VERSION 5.7 ;
  NOWIREEXTENSIONATPIN ON ;
  DIVIDERCHAR "/" ;
  BUSBITCHARS "[]" ;
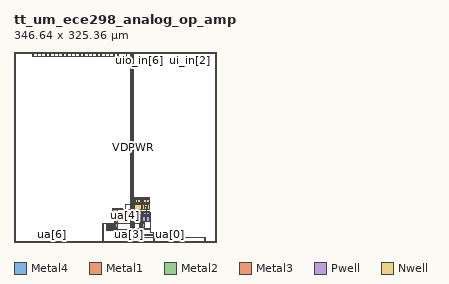
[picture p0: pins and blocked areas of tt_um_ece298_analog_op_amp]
MACRO tt_um_ece298_analog_op_amp
  CLASS BLOCK ;
  FOREIGN tt_um_ece298_analog_op_amp ;
  ORIGIN 0.000 0.000 ;
  SIZE 346.640 BY 325.360 ;
  PIN clk
    DIRECTION INPUT ;
    USE SIGNAL ;
    PORT
      LAYER Metal4 ;
        RECT 331.090 324.360 331.390 325.360 ;
    END
  END clk
  PIN ena
    DIRECTION INPUT ;
    USE SIGNAL ;
    PORT
      LAYER Metal4 ;
        RECT 338.370 324.360 338.670 325.360 ;
    END
  END ena
  PIN rst_n
    DIRECTION INPUT ;
    USE SIGNAL ;
    PORT
      LAYER Metal4 ;
        RECT 323.810 324.360 324.110 325.360 ;
    END
  END rst_n
  PIN ua[0]
    DIRECTION INOUT ;
    USE SIGNAL ;
    ANTENNAGATEAREA 44.799999 ;
    PORT
      LAYER Metal1 ;
        RECT 207.330 43.515 208.710 43.745 ;
        RECT 209.250 43.515 210.630 43.745 ;
        RECT 227.790 43.515 229.170 43.745 ;
        RECT 229.710 43.515 231.090 43.745 ;
        RECT 207.840 43.450 208.220 43.515 ;
        RECT 209.750 43.450 210.130 43.515 ;
        RECT 228.300 43.450 228.680 43.515 ;
        RECT 230.210 43.450 230.590 43.515 ;
        RECT 207.330 34.955 208.710 35.185 ;
        RECT 209.250 34.955 210.630 35.185 ;
        RECT 227.790 34.955 229.170 35.185 ;
        RECT 229.710 34.955 231.090 35.185 ;
      LAYER Metal2 ;
        RECT 205.230 45.550 205.730 45.650 ;
        RECT 205.230 45.250 228.680 45.550 ;
        RECT 205.230 45.150 205.730 45.250 ;
        RECT 207.840 43.820 208.220 45.250 ;
        RECT 228.300 43.820 228.680 45.250 ;
        RECT 207.380 43.520 210.580 43.820 ;
        RECT 227.840 43.520 231.040 43.820 ;
        RECT 207.840 43.450 208.220 43.520 ;
        RECT 209.750 43.450 210.130 43.520 ;
        RECT 228.300 43.450 228.680 43.520 ;
        RECT 230.210 43.450 230.590 43.520 ;
      LAYER Metal3 ;
        RECT 205.230 45.150 205.730 45.650 ;
        RECT 205.280 8.250 205.680 45.150 ;
        RECT 205.280 7.750 327.570 8.250 ;
      LAYER Metal4 ;
        RECT 326.820 1.000 327.820 8.250 ;
        RECT 325.820 0.000 328.820 1.000 ;
    END
  END ua[0]
  PIN ua[1]
    DIRECTION INOUT ;
    USE SIGNAL ;
    ANTENNAGATEAREA 44.799999 ;
    PORT
      LAYER Metal1 ;
        RECT 214.150 43.515 215.530 43.745 ;
        RECT 216.070 43.515 217.450 43.745 ;
        RECT 220.970 43.515 222.350 43.745 ;
        RECT 222.890 43.515 224.270 43.745 ;
        RECT 214.660 43.450 215.040 43.515 ;
        RECT 216.570 43.450 216.950 43.515 ;
        RECT 221.480 43.450 221.860 43.515 ;
        RECT 223.390 43.450 223.770 43.515 ;
        RECT 214.150 34.955 215.530 35.185 ;
        RECT 216.070 34.955 217.450 35.185 ;
        RECT 220.970 34.955 222.350 35.185 ;
        RECT 222.890 34.955 224.270 35.185 ;
      LAYER Metal2 ;
        RECT 216.570 43.820 217.580 43.840 ;
        RECT 214.200 43.740 217.580 43.820 ;
        RECT 221.020 43.740 224.220 43.820 ;
        RECT 214.200 43.520 224.220 43.740 ;
        RECT 214.660 43.450 215.040 43.520 ;
        RECT 216.570 43.450 221.860 43.520 ;
        RECT 223.390 43.450 223.770 43.520 ;
        RECT 216.570 43.350 217.580 43.450 ;
      LAYER Metal3 ;
        RECT 217.080 12.250 217.480 43.840 ;
        RECT 217.080 11.750 283.890 12.250 ;
      LAYER Metal4 ;
        RECT 283.140 1.000 284.140 12.250 ;
        RECT 282.140 0.000 285.140 1.000 ;
    END
  END ua[1]
  PIN ua[2]
    DIRECTION INOUT ;
    USE SIGNAL ;
    ANTENNADIFFAREA 12.880000 ;
    PORT
      LAYER Metal1 ;
        RECT 223.625 61.090 223.855 63.540 ;
        RECT 228.665 61.090 228.895 63.540 ;
        RECT 223.590 60.710 223.910 61.090 ;
        RECT 228.650 60.710 228.970 61.090 ;
        RECT 223.625 56.560 223.855 60.710 ;
        RECT 228.665 56.560 228.895 60.710 ;
        RECT 221.105 50.490 221.335 51.440 ;
        RECT 226.145 50.490 226.375 51.440 ;
        RECT 231.185 50.490 231.415 51.440 ;
        RECT 221.060 50.110 221.380 50.490 ;
        RECT 226.120 50.110 226.440 50.490 ;
        RECT 231.180 50.110 231.500 50.490 ;
        RECT 221.105 47.460 221.335 50.110 ;
        RECT 226.145 47.460 226.375 50.110 ;
        RECT 231.185 47.460 231.415 50.110 ;
      LAYER Metal2 ;
        RECT 223.560 60.750 229.000 61.050 ;
        RECT 233.030 50.450 233.530 50.550 ;
        RECT 221.030 50.150 233.530 50.450 ;
        RECT 233.030 50.050 233.530 50.150 ;
      LAYER Metal3 ;
        RECT 226.780 50.100 227.180 61.110 ;
        RECT 233.030 50.050 233.530 50.550 ;
        RECT 233.080 16.250 233.480 50.050 ;
        RECT 233.080 15.750 240.210 16.250 ;
      LAYER Metal4 ;
        RECT 239.460 1.000 240.460 16.250 ;
        RECT 238.460 0.000 241.460 1.000 ;
    END
  END ua[2]
  PIN ua[3]
    DIRECTION INOUT ;
    USE SIGNAL ;
    PORT
      LAYER Metal4 ;
        RECT 194.780 0.000 197.780 1.000 ;
    END
  END ua[3]
  PIN ua[4]
    DIRECTION INOUT ;
    USE SIGNAL ;
    ANTENNAGATEAREA 100.799995 ;
    ANTENNADIFFAREA 8.320000 ;
    PORT
      LAYER Metal1 ;
        RECT 159.570 31.645 159.930 31.650 ;
        RECT 161.490 31.645 161.850 31.650 ;
        RECT 163.410 31.645 163.770 31.650 ;
        RECT 165.330 31.645 165.690 31.650 ;
        RECT 159.060 31.415 160.440 31.645 ;
        RECT 160.980 31.415 162.360 31.645 ;
        RECT 162.900 31.415 164.280 31.645 ;
        RECT 164.820 31.415 166.200 31.645 ;
        RECT 169.940 31.415 171.320 31.645 ;
        RECT 215.640 31.415 217.020 31.645 ;
        RECT 217.560 31.415 218.940 31.645 ;
        RECT 219.480 31.415 220.860 31.645 ;
        RECT 221.400 31.415 222.780 31.645 ;
        RECT 159.560 31.350 159.940 31.415 ;
        RECT 161.480 31.350 161.860 31.415 ;
        RECT 163.400 31.350 163.780 31.415 ;
        RECT 165.320 31.350 165.700 31.415 ;
        RECT 170.155 31.345 171.105 31.415 ;
        RECT 216.140 31.350 216.520 31.415 ;
        RECT 218.060 31.350 218.440 31.415 ;
        RECT 219.980 31.350 220.360 31.415 ;
        RECT 221.900 31.350 222.280 31.415 ;
        RECT 160.595 28.380 160.825 31.240 ;
        RECT 164.435 28.380 164.665 31.240 ;
        RECT 160.530 28.020 160.890 28.380 ;
        RECT 164.370 28.020 164.730 28.380 ;
        RECT 160.595 23.260 160.825 28.020 ;
        RECT 164.435 23.260 164.665 28.020 ;
        RECT 159.060 22.855 160.440 23.085 ;
        RECT 160.980 22.855 162.360 23.085 ;
        RECT 162.900 22.855 164.280 23.085 ;
        RECT 164.820 22.855 166.200 23.085 ;
        RECT 169.940 22.855 171.320 23.085 ;
        RECT 215.640 22.855 217.020 23.085 ;
        RECT 217.560 22.855 218.940 23.085 ;
        RECT 219.480 22.855 220.860 23.085 ;
        RECT 221.400 22.855 222.780 23.085 ;
      LAYER Metal2 ;
        RECT 157.500 31.700 158.200 31.800 ;
        RECT 157.500 31.650 206.430 31.700 ;
        RECT 216.140 31.650 222.280 31.700 ;
        RECT 157.500 31.350 222.280 31.650 ;
        RECT 157.500 31.300 206.430 31.350 ;
        RECT 157.500 31.200 158.200 31.300 ;
        RECT 160.560 28.400 160.860 31.300 ;
        RECT 164.400 28.400 164.700 31.300 ;
        RECT 160.520 28.000 160.900 28.400 ;
        RECT 164.360 28.000 164.740 28.400 ;
      LAYER Metal3 ;
        RECT 157.500 31.750 158.200 31.800 ;
        RECT 152.350 31.250 158.200 31.750 ;
        RECT 152.350 2.400 152.850 31.250 ;
        RECT 157.500 31.200 158.200 31.250 ;
        RECT 152.100 0.500 153.100 2.400 ;
      LAYER Metal4 ;
        RECT 152.100 1.000 153.100 2.400 ;
        RECT 151.100 0.000 154.100 1.000 ;
    END
  END ua[4]
  PIN ua[5]
    DIRECTION INOUT ;
    USE SIGNAL ;
    PORT
      LAYER Metal4 ;
        RECT 107.420 0.000 110.420 1.000 ;
    END
  END ua[5]
  PIN ua[6]
    DIRECTION INOUT ;
    USE SIGNAL ;
    PORT
      LAYER Metal4 ;
        RECT 63.740 0.000 66.740 1.000 ;
    END
  END ua[6]
  PIN ua[7]
    DIRECTION INOUT ;
    USE SIGNAL ;
    PORT
      LAYER Metal4 ;
        RECT 20.060 0.000 23.060 1.000 ;
    END
  END ua[7]
  PIN ui_in[0]
    DIRECTION INPUT ;
    USE SIGNAL ;
    PORT
      LAYER Metal4 ;
        RECT 316.530 324.360 316.830 325.360 ;
    END
  END ui_in[0]
  PIN ui_in[1]
    DIRECTION INPUT ;
    USE SIGNAL ;
    PORT
      LAYER Metal4 ;
        RECT 309.250 324.360 309.550 325.360 ;
    END
  END ui_in[1]
  PIN ui_in[2]
    DIRECTION INPUT ;
    USE SIGNAL ;
    PORT
      LAYER Metal4 ;
        RECT 301.970 324.360 302.270 325.360 ;
    END
  END ui_in[2]
  PIN ui_in[3]
    DIRECTION INPUT ;
    USE SIGNAL ;
    PORT
      LAYER Metal4 ;
        RECT 294.690 324.360 294.990 325.360 ;
    END
  END ui_in[3]
  PIN ui_in[4]
    DIRECTION INPUT ;
    USE SIGNAL ;
    PORT
      LAYER Metal4 ;
        RECT 287.410 324.360 287.710 325.360 ;
    END
  END ui_in[4]
  PIN ui_in[5]
    DIRECTION INPUT ;
    USE SIGNAL ;
    PORT
      LAYER Metal4 ;
        RECT 280.130 324.360 280.430 325.360 ;
    END
  END ui_in[5]
  PIN ui_in[6]
    DIRECTION INPUT ;
    USE SIGNAL ;
    PORT
      LAYER Metal4 ;
        RECT 272.850 324.360 273.150 325.360 ;
    END
  END ui_in[6]
  PIN ui_in[7]
    DIRECTION INPUT ;
    USE SIGNAL ;
    PORT
      LAYER Metal4 ;
        RECT 265.570 324.360 265.870 325.360 ;
    END
  END ui_in[7]
  PIN uio_in[0]
    DIRECTION INPUT ;
    USE SIGNAL ;
    PORT
      LAYER Metal4 ;
        RECT 258.290 324.360 258.590 325.360 ;
    END
  END uio_in[0]
  PIN uio_in[1]
    DIRECTION INPUT ;
    USE SIGNAL ;
    PORT
      LAYER Metal4 ;
        RECT 251.010 324.360 251.310 325.360 ;
    END
  END uio_in[1]
  PIN uio_in[2]
    DIRECTION INPUT ;
    USE SIGNAL ;
    PORT
      LAYER Metal4 ;
        RECT 243.730 324.360 244.030 325.360 ;
    END
  END uio_in[2]
  PIN uio_in[3]
    DIRECTION INPUT ;
    USE SIGNAL ;
    PORT
      LAYER Metal4 ;
        RECT 236.450 324.360 236.750 325.360 ;
    END
  END uio_in[3]
  PIN uio_in[4]
    DIRECTION INPUT ;
    USE SIGNAL ;
    PORT
      LAYER Metal4 ;
        RECT 229.170 324.360 229.470 325.360 ;
    END
  END uio_in[4]
  PIN uio_in[5]
    DIRECTION INPUT ;
    USE SIGNAL ;
    PORT
      LAYER Metal4 ;
        RECT 221.890 324.360 222.190 325.360 ;
    END
  END uio_in[5]
  PIN uio_in[6]
    DIRECTION INPUT ;
    USE SIGNAL ;
    PORT
      LAYER Metal4 ;
        RECT 214.610 324.360 214.910 325.360 ;
    END
  END uio_in[6]
  PIN uio_in[7]
    DIRECTION INPUT ;
    USE SIGNAL ;
    PORT
      LAYER Metal4 ;
        RECT 207.330 324.360 207.630 325.360 ;
    END
  END uio_in[7]
  PIN uio_oe[0]
    DIRECTION OUTPUT ;
    USE SIGNAL ;
    ANTENNADIFFAREA 147.982391 ;
    PORT
      LAYER Pwell ;
        RECT 206.130 46.400 218.190 52.500 ;
        RECT 220.230 46.400 232.290 52.500 ;
        RECT 173.680 35.950 177.580 46.050 ;
        RECT 157.800 22.200 167.460 32.300 ;
        RECT 168.680 22.200 172.580 32.300 ;
        RECT 174.080 23.000 177.180 34.500 ;
        RECT 206.070 34.300 211.890 44.400 ;
        RECT 212.890 34.300 218.710 44.400 ;
        RECT 219.710 34.300 225.530 44.400 ;
        RECT 226.530 34.300 232.350 44.400 ;
        RECT 214.380 22.200 224.040 32.300 ;
      LAYER Metal1 ;
        RECT 206.315 52.085 218.005 52.315 ;
        RECT 206.315 46.815 206.545 52.085 ;
        RECT 217.775 46.815 218.005 52.085 ;
        RECT 206.315 46.585 218.005 46.815 ;
        RECT 220.415 52.085 232.105 52.315 ;
        RECT 220.415 46.815 220.645 52.085 ;
        RECT 231.875 46.815 232.105 52.085 ;
        RECT 220.415 46.585 232.105 46.815 ;
        RECT 173.865 45.635 177.395 45.865 ;
        RECT 173.865 36.430 174.095 45.635 ;
        RECT 177.165 36.430 177.395 45.635 ;
        RECT 206.320 44.550 206.570 46.585 ;
        RECT 231.850 44.550 232.100 46.585 ;
        RECT 206.130 44.020 232.290 44.550 ;
        RECT 173.865 36.365 174.280 36.430 ;
        RECT 176.980 36.365 177.395 36.430 ;
        RECT 173.865 34.100 177.395 36.365 ;
        RECT 206.255 43.985 211.705 44.020 ;
        RECT 206.255 34.715 206.485 43.985 ;
        RECT 211.475 34.715 211.705 43.985 ;
        RECT 206.255 34.485 211.705 34.715 ;
        RECT 213.075 43.985 218.525 44.020 ;
        RECT 213.075 34.715 213.305 43.985 ;
        RECT 218.295 34.715 218.525 43.985 ;
        RECT 213.075 34.485 218.525 34.715 ;
        RECT 219.895 43.985 225.345 44.020 ;
        RECT 219.895 34.715 220.125 43.985 ;
        RECT 225.115 34.715 225.345 43.985 ;
        RECT 219.895 34.485 225.345 34.715 ;
        RECT 226.715 43.985 232.165 44.020 ;
        RECT 226.715 34.715 226.945 43.985 ;
        RECT 231.935 34.715 232.165 43.985 ;
        RECT 226.715 34.485 232.165 34.715 ;
        RECT 173.865 34.085 177.400 34.100 ;
        RECT 173.865 33.865 174.495 34.085 ;
        RECT 173.860 32.115 174.495 33.865 ;
        RECT 157.985 31.885 174.495 32.115 ;
        RECT 157.985 31.240 158.215 31.885 ;
        RECT 167.045 31.240 169.095 31.885 ;
        RECT 157.985 25.380 158.905 31.240 ;
        RECT 162.515 25.380 162.745 31.240 ;
        RECT 166.355 28.800 169.095 31.240 ;
        RECT 166.355 27.440 169.130 28.800 ;
        RECT 169.555 27.440 169.785 31.240 ;
        RECT 166.355 27.040 169.785 27.440 ;
        RECT 166.355 25.380 169.130 27.040 ;
        RECT 157.985 25.020 158.970 25.380 ;
        RECT 162.450 25.020 162.810 25.380 ;
        RECT 166.290 25.020 169.130 25.380 ;
        RECT 157.985 23.260 158.905 25.020 ;
        RECT 162.515 23.260 162.745 25.020 ;
        RECT 166.355 24.135 169.130 25.020 ;
        RECT 166.355 23.260 169.095 24.135 ;
        RECT 169.555 23.260 169.785 27.040 ;
        RECT 172.165 24.000 174.495 31.885 ;
        RECT 175.140 24.000 176.120 24.105 ;
        RECT 176.765 24.000 177.400 34.085 ;
        RECT 214.570 32.550 214.820 34.485 ;
        RECT 223.600 32.550 223.850 34.485 ;
        RECT 214.380 32.020 224.040 32.550 ;
        RECT 157.985 22.615 158.215 23.260 ;
        RECT 167.045 22.615 169.095 23.260 ;
        RECT 172.165 22.615 177.400 24.000 ;
        RECT 157.985 22.385 177.400 22.615 ;
        RECT 214.565 31.885 223.855 32.020 ;
        RECT 214.565 22.615 214.795 31.885 ;
        RECT 215.255 25.390 215.485 31.240 ;
        RECT 219.095 25.390 219.325 31.240 ;
        RECT 222.935 25.390 223.165 31.240 ;
        RECT 215.210 25.010 215.530 25.390 ;
        RECT 219.050 25.010 219.370 25.390 ;
        RECT 222.890 25.010 223.210 25.390 ;
        RECT 215.255 23.260 215.485 25.010 ;
        RECT 219.095 23.260 219.325 25.010 ;
        RECT 222.935 23.260 223.165 25.010 ;
        RECT 223.625 22.615 223.855 31.885 ;
        RECT 214.565 22.500 223.855 22.615 ;
        RECT 157.980 21.500 177.400 22.385 ;
        RECT 206.130 21.500 232.290 22.500 ;
        RECT 157.980 20.900 232.290 21.500 ;
        RECT 157.980 20.250 186.430 20.900 ;
      LAYER Metal2 ;
        RECT 158.530 25.050 166.730 25.350 ;
        RECT 215.180 25.050 223.240 25.350 ;
        RECT 162.440 21.500 162.820 25.050 ;
        RECT 198.000 21.500 199.200 21.550 ;
        RECT 206.130 21.500 232.290 22.400 ;
        RECT 157.980 20.900 232.290 21.500 ;
        RECT 198.000 20.850 199.200 20.900 ;
      LAYER Metal3 ;
        RECT 32.260 317.500 200.500 318.500 ;
        RECT 217.880 21.940 218.280 25.400 ;
        RECT 198.400 20.850 200.400 21.550 ;
      LAYER Metal4 ;
        RECT 32.460 317.500 33.060 325.360 ;
        RECT 39.740 317.500 40.340 325.360 ;
        RECT 47.020 317.500 47.620 325.360 ;
        RECT 54.300 317.500 54.900 325.360 ;
        RECT 61.580 317.500 62.180 325.360 ;
        RECT 68.860 317.500 69.460 325.360 ;
        RECT 76.140 317.500 76.740 325.360 ;
        RECT 83.420 317.500 84.020 325.360 ;
        RECT 90.700 317.500 91.300 325.360 ;
        RECT 97.980 317.500 98.580 325.360 ;
        RECT 105.260 317.500 105.860 325.360 ;
        RECT 112.540 317.500 113.140 325.360 ;
        RECT 119.820 317.500 120.420 325.360 ;
        RECT 127.100 317.500 127.700 325.360 ;
        RECT 134.380 317.500 134.980 325.360 ;
        RECT 141.660 317.500 142.260 325.360 ;
        RECT 148.940 317.500 149.540 325.360 ;
        RECT 156.220 317.500 156.820 325.360 ;
        RECT 163.500 317.500 164.100 325.360 ;
        RECT 170.780 317.500 171.380 325.360 ;
        RECT 178.060 317.500 178.660 325.360 ;
        RECT 185.340 317.500 185.940 325.360 ;
        RECT 192.620 317.500 193.220 325.360 ;
        RECT 199.900 320.360 200.500 325.360 ;
        RECT 198.780 5.000 200.780 320.360 ;
    END
  END uio_oe[0]
  PIN VDPWR
    DIRECTION INOUT ;
    USE POWER ;
    PORT
      LAYER Nwell ;
        RECT 206.130 66.600 218.190 75.700 ;
        RECT 220.230 66.600 232.290 75.700 ;
        RECT 206.130 55.500 218.190 64.600 ;
        RECT 220.230 55.500 232.290 64.600 ;
        RECT 168.680 47.250 177.580 50.750 ;
      LAYER Metal1 ;
        RECT 201.680 75.400 232.290 76.900 ;
        RECT 168.730 56.250 186.430 56.750 ;
        RECT 201.680 56.250 202.880 75.400 ;
        RECT 206.315 75.285 218.005 75.400 ;
        RECT 206.315 67.015 206.545 75.285 ;
        RECT 207.005 73.690 207.235 74.640 ;
        RECT 212.045 73.690 212.275 74.640 ;
        RECT 217.085 73.690 217.315 74.640 ;
        RECT 206.960 73.310 207.280 73.690 ;
        RECT 212.020 73.310 212.340 73.690 ;
        RECT 217.080 73.310 217.400 73.690 ;
        RECT 207.005 67.660 207.235 73.310 ;
        RECT 212.045 67.660 212.275 73.310 ;
        RECT 217.085 67.660 217.315 73.310 ;
        RECT 217.775 67.015 218.005 75.285 ;
        RECT 206.315 66.785 218.005 67.015 ;
        RECT 220.415 75.285 232.105 75.400 ;
        RECT 220.415 67.015 220.645 75.285 ;
        RECT 221.105 73.690 221.335 74.640 ;
        RECT 226.145 73.690 226.375 74.640 ;
        RECT 231.185 73.690 231.415 74.640 ;
        RECT 221.060 73.310 221.380 73.690 ;
        RECT 226.120 73.310 226.440 73.690 ;
        RECT 231.180 73.310 231.500 73.690 ;
        RECT 221.105 67.660 221.335 73.310 ;
        RECT 226.145 67.660 226.375 73.310 ;
        RECT 231.185 67.660 231.415 73.310 ;
        RECT 231.875 67.015 232.105 75.285 ;
        RECT 220.415 66.785 232.105 67.015 ;
        RECT 206.320 64.415 206.570 66.785 ;
        RECT 231.850 64.415 232.100 66.785 ;
        RECT 168.730 55.650 202.880 56.250 ;
        RECT 206.315 64.185 218.005 64.415 ;
        RECT 206.315 55.915 206.545 64.185 ;
        RECT 208.620 63.945 209.000 63.950 ;
        RECT 207.390 63.715 209.370 63.945 ;
        RECT 209.910 63.715 211.890 63.945 ;
        RECT 212.430 63.715 214.410 63.945 ;
        RECT 214.950 63.715 216.930 63.945 ;
        RECT 208.620 63.660 209.015 63.715 ;
        RECT 208.635 63.650 209.015 63.660 ;
        RECT 210.120 63.650 210.500 63.715 ;
        RECT 213.460 63.650 213.840 63.715 ;
        RECT 216.160 63.650 216.540 63.715 ;
        RECT 207.390 56.155 209.370 56.385 ;
        RECT 209.910 56.155 211.890 56.385 ;
        RECT 212.430 56.155 214.410 56.385 ;
        RECT 214.950 56.155 216.930 56.385 ;
        RECT 217.775 55.915 218.005 64.185 ;
        RECT 206.315 55.685 218.005 55.915 ;
        RECT 220.415 64.185 232.105 64.415 ;
        RECT 220.415 55.915 220.645 64.185 ;
        RECT 222.720 63.945 223.100 63.950 ;
        RECT 221.490 63.715 223.470 63.945 ;
        RECT 224.010 63.715 225.990 63.945 ;
        RECT 226.530 63.715 228.510 63.945 ;
        RECT 229.050 63.715 231.030 63.945 ;
        RECT 222.720 63.660 223.115 63.715 ;
        RECT 222.735 63.650 223.115 63.660 ;
        RECT 224.220 63.650 224.600 63.715 ;
        RECT 227.560 63.650 227.940 63.715 ;
        RECT 230.260 63.650 230.640 63.715 ;
        RECT 221.490 56.155 223.470 56.385 ;
        RECT 224.010 56.155 225.990 56.385 ;
        RECT 226.530 56.155 228.510 56.385 ;
        RECT 229.050 56.155 231.030 56.385 ;
        RECT 231.875 55.915 232.105 64.185 ;
        RECT 220.415 55.685 232.105 55.915 ;
        RECT 168.730 55.250 186.430 55.650 ;
        RECT 168.730 50.135 177.530 55.250 ;
        RECT 168.730 49.200 169.130 50.135 ;
        RECT 169.940 49.665 171.320 49.895 ;
        RECT 169.555 49.200 169.785 49.490 ;
        RECT 171.475 49.200 171.705 49.490 ;
        RECT 168.730 48.800 169.785 49.200 ;
        RECT 171.390 48.800 171.790 49.200 ;
        RECT 168.730 47.865 169.130 48.800 ;
        RECT 169.555 48.510 169.785 48.800 ;
        RECT 171.475 48.510 171.705 48.800 ;
        RECT 170.155 48.335 171.105 48.430 ;
        RECT 169.940 48.105 171.320 48.335 ;
        RECT 172.165 47.865 172.395 50.135 ;
        RECT 173.865 49.200 174.095 50.135 ;
        RECT 174.940 49.665 176.320 49.895 ;
        RECT 174.555 49.200 174.785 49.490 ;
        RECT 173.780 48.800 174.785 49.200 ;
        RECT 173.865 47.865 174.095 48.800 ;
        RECT 174.555 48.510 174.785 48.800 ;
        RECT 175.155 48.335 176.105 48.430 ;
        RECT 174.940 48.105 176.320 48.335 ;
        RECT 177.130 47.865 177.530 50.135 ;
        RECT 168.730 47.635 177.530 47.865 ;
        RECT 171.475 29.850 171.705 31.240 ;
        RECT 171.390 27.650 171.790 29.850 ;
        RECT 171.475 23.260 171.705 27.650 ;
      LAYER Metal2 ;
        RECT 201.680 75.700 232.290 76.900 ;
        RECT 201.680 64.000 202.880 75.700 ;
        RECT 206.130 75.500 232.290 75.700 ;
        RECT 206.930 73.350 217.430 73.650 ;
        RECT 221.030 73.350 231.530 73.650 ;
        RECT 190.080 63.950 206.430 64.000 ;
        RECT 208.380 63.950 210.980 64.000 ;
        RECT 211.330 63.950 213.180 64.020 ;
        RECT 213.480 63.950 215.780 64.010 ;
        RECT 216.080 64.000 222.780 64.050 ;
        RECT 216.080 63.950 225.080 64.000 ;
        RECT 225.430 63.950 227.280 64.020 ;
        RECT 227.580 63.950 229.880 64.010 ;
        RECT 230.250 63.950 230.630 63.960 ;
        RECT 190.080 63.650 230.780 63.950 ;
        RECT 190.080 63.600 206.430 63.650 ;
        RECT 190.080 56.250 190.480 63.600 ;
        RECT 201.680 56.250 202.880 63.600 ;
        RECT 216.080 63.550 222.780 63.650 ;
        RECT 168.730 55.650 202.880 56.250 ;
        RECT 171.390 48.500 171.790 49.200 ;
        RECT 190.080 48.500 190.480 55.650 ;
        RECT 169.980 48.100 190.480 48.500 ;
        RECT 171.380 27.600 171.800 29.850 ;
      LAYER Metal3 ;
        RECT 203.200 75.700 205.000 76.600 ;
        RECT 213.480 73.300 213.880 76.540 ;
        RECT 227.580 73.300 227.980 76.540 ;
        RECT 171.390 27.650 171.790 49.200 ;
      LAYER Metal4 ;
        RECT 203.080 5.000 205.080 320.360 ;
    END
  END VDPWR
  OBS
      LAYER Metal1 ;
        RECT 208.620 75.045 209.000 75.050 ;
        RECT 222.720 75.045 223.100 75.050 ;
        RECT 207.390 74.815 209.370 75.045 ;
        RECT 209.910 74.815 211.890 75.045 ;
        RECT 212.430 74.815 214.410 75.045 ;
        RECT 214.950 74.815 216.930 75.045 ;
        RECT 221.490 74.815 223.470 75.045 ;
        RECT 224.010 74.815 225.990 75.045 ;
        RECT 226.530 74.815 228.510 75.045 ;
        RECT 229.050 74.815 231.030 75.045 ;
        RECT 208.620 74.760 209.015 74.815 ;
        RECT 208.635 74.750 209.015 74.760 ;
        RECT 210.120 74.750 210.500 74.815 ;
        RECT 213.460 74.750 213.840 74.815 ;
        RECT 216.160 74.750 216.540 74.815 ;
        RECT 222.720 74.760 223.115 74.815 ;
        RECT 222.735 74.750 223.115 74.760 ;
        RECT 224.220 74.750 224.600 74.815 ;
        RECT 227.560 74.750 227.940 74.815 ;
        RECT 230.260 74.750 230.640 74.815 ;
        RECT 209.525 72.190 209.755 74.640 ;
        RECT 214.565 72.190 214.795 74.640 ;
        RECT 223.625 72.190 223.855 74.640 ;
        RECT 228.665 72.190 228.895 74.640 ;
        RECT 209.490 71.810 209.810 72.190 ;
        RECT 214.550 71.810 214.870 72.190 ;
        RECT 223.590 71.810 223.910 72.190 ;
        RECT 228.650 71.810 228.970 72.190 ;
        RECT 209.525 67.660 209.755 71.810 ;
        RECT 214.565 67.660 214.795 71.810 ;
        RECT 223.625 67.660 223.855 71.810 ;
        RECT 228.665 67.660 228.895 71.810 ;
        RECT 207.390 67.255 209.370 67.485 ;
        RECT 209.910 67.255 211.890 67.485 ;
        RECT 212.430 67.255 214.410 67.485 ;
        RECT 214.950 67.255 216.930 67.485 ;
        RECT 221.490 67.255 223.470 67.485 ;
        RECT 224.010 67.255 225.990 67.485 ;
        RECT 226.530 67.255 228.510 67.485 ;
        RECT 229.050 67.255 231.030 67.485 ;
        RECT 207.005 62.590 207.235 63.540 ;
        RECT 206.960 62.210 207.280 62.590 ;
        RECT 207.005 56.560 207.235 62.210 ;
        RECT 209.525 61.090 209.755 63.540 ;
        RECT 212.045 62.590 212.275 63.540 ;
        RECT 212.020 62.210 212.340 62.590 ;
        RECT 209.490 60.710 209.810 61.090 ;
        RECT 209.525 56.560 209.755 60.710 ;
        RECT 212.045 56.560 212.275 62.210 ;
        RECT 214.565 61.090 214.795 63.540 ;
        RECT 217.085 62.590 217.315 63.540 ;
        RECT 221.105 62.590 221.335 63.540 ;
        RECT 226.145 62.590 226.375 63.540 ;
        RECT 231.185 62.590 231.415 63.540 ;
        RECT 217.080 62.210 217.400 62.590 ;
        RECT 221.060 62.210 221.380 62.590 ;
        RECT 226.120 62.210 226.440 62.590 ;
        RECT 231.180 62.210 231.500 62.590 ;
        RECT 214.550 60.710 214.870 61.090 ;
        RECT 214.565 56.560 214.795 60.710 ;
        RECT 217.085 56.560 217.315 62.210 ;
        RECT 221.105 56.560 221.335 62.210 ;
        RECT 226.145 56.560 226.375 62.210 ;
        RECT 231.185 56.560 231.415 62.210 ;
        RECT 208.620 51.845 209.000 51.850 ;
        RECT 222.720 51.845 223.100 51.850 ;
        RECT 207.390 51.615 209.370 51.845 ;
        RECT 209.910 51.615 211.890 51.845 ;
        RECT 212.430 51.615 214.410 51.845 ;
        RECT 214.950 51.615 216.930 51.845 ;
        RECT 221.490 51.615 223.470 51.845 ;
        RECT 224.010 51.615 225.990 51.845 ;
        RECT 226.530 51.615 228.510 51.845 ;
        RECT 229.050 51.615 231.030 51.845 ;
        RECT 208.620 51.560 209.015 51.615 ;
        RECT 208.635 51.550 209.015 51.560 ;
        RECT 210.120 51.550 210.500 51.615 ;
        RECT 213.460 51.550 213.840 51.615 ;
        RECT 216.160 51.550 216.540 51.615 ;
        RECT 222.720 51.560 223.115 51.615 ;
        RECT 222.735 51.550 223.115 51.560 ;
        RECT 224.220 51.550 224.600 51.615 ;
        RECT 227.560 51.550 227.940 51.615 ;
        RECT 230.260 51.550 230.640 51.615 ;
        RECT 207.005 50.490 207.235 51.440 ;
        RECT 206.960 50.110 207.280 50.490 ;
        RECT 176.475 49.200 176.705 49.490 ;
        RECT 176.390 48.800 176.790 49.200 ;
        RECT 176.475 48.510 176.705 48.800 ;
        RECT 207.005 47.460 207.235 50.110 ;
        RECT 209.525 48.990 209.755 51.440 ;
        RECT 212.045 50.490 212.275 51.440 ;
        RECT 212.020 50.110 212.340 50.490 ;
        RECT 209.490 48.610 209.810 48.990 ;
        RECT 209.525 47.460 209.755 48.610 ;
        RECT 212.045 47.460 212.275 50.110 ;
        RECT 214.565 48.990 214.795 51.440 ;
        RECT 217.085 50.490 217.315 51.440 ;
        RECT 217.080 50.110 217.400 50.490 ;
        RECT 214.550 48.610 214.870 48.990 ;
        RECT 214.565 47.460 214.795 48.610 ;
        RECT 217.085 47.460 217.315 50.110 ;
        RECT 223.625 48.990 223.855 51.440 ;
        RECT 228.665 48.990 228.895 51.440 ;
        RECT 223.590 48.610 223.910 48.990 ;
        RECT 228.650 48.610 228.970 48.990 ;
        RECT 223.625 47.460 223.855 48.610 ;
        RECT 228.665 47.460 228.895 48.610 ;
        RECT 207.390 47.055 209.370 47.285 ;
        RECT 209.910 47.055 211.890 47.285 ;
        RECT 212.430 47.055 214.410 47.285 ;
        RECT 214.950 47.055 216.930 47.285 ;
        RECT 221.490 47.055 223.470 47.285 ;
        RECT 224.010 47.055 225.990 47.285 ;
        RECT 226.530 47.055 228.510 47.285 ;
        RECT 229.050 47.055 231.030 47.285 ;
        RECT 174.940 45.165 176.320 45.395 ;
        RECT 175.155 45.120 176.105 45.165 ;
        RECT 174.555 40.850 174.785 44.990 ;
        RECT 174.470 38.650 174.870 40.850 ;
        RECT 176.475 40.600 176.705 44.990 ;
        RECT 174.555 37.010 174.785 38.650 ;
        RECT 176.390 38.400 176.790 40.600 ;
        RECT 176.475 37.010 176.705 38.400 ;
        RECT 206.945 37.490 207.175 43.340 ;
        RECT 208.865 42.190 209.095 43.340 ;
        RECT 208.820 41.810 209.140 42.190 ;
        RECT 206.890 37.110 207.210 37.490 ;
        RECT 174.940 36.605 176.320 36.835 ;
        RECT 206.945 35.360 207.175 37.110 ;
        RECT 208.865 35.360 209.095 41.810 ;
        RECT 210.785 37.490 211.015 43.340 ;
        RECT 213.765 37.490 213.995 43.340 ;
        RECT 215.685 40.690 215.915 43.340 ;
        RECT 215.640 40.310 215.960 40.690 ;
        RECT 210.760 37.110 211.080 37.490 ;
        RECT 213.710 37.110 214.030 37.490 ;
        RECT 210.785 35.360 211.015 37.110 ;
        RECT 213.765 35.360 213.995 37.110 ;
        RECT 215.685 35.360 215.915 40.310 ;
        RECT 217.605 37.490 217.835 43.340 ;
        RECT 220.585 37.490 220.815 43.340 ;
        RECT 222.505 40.690 222.735 43.340 ;
        RECT 222.460 40.310 222.780 40.690 ;
        RECT 217.580 37.110 217.900 37.490 ;
        RECT 220.530 37.110 220.850 37.490 ;
        RECT 217.605 35.360 217.835 37.110 ;
        RECT 220.585 35.360 220.815 37.110 ;
        RECT 222.505 35.360 222.735 40.310 ;
        RECT 224.425 37.490 224.655 43.340 ;
        RECT 227.405 37.490 227.635 43.340 ;
        RECT 229.325 42.190 229.555 43.340 ;
        RECT 229.280 41.810 229.600 42.190 ;
        RECT 224.400 37.110 224.720 37.490 ;
        RECT 227.350 37.110 227.670 37.490 ;
        RECT 224.425 35.360 224.655 37.110 ;
        RECT 227.405 35.360 227.635 37.110 ;
        RECT 229.325 35.360 229.555 41.810 ;
        RECT 231.245 37.490 231.475 43.340 ;
        RECT 231.220 37.110 231.540 37.490 ;
        RECT 231.245 35.360 231.475 37.110 ;
        RECT 175.430 33.625 175.830 33.700 ;
        RECT 175.140 33.395 176.120 33.625 ;
        RECT 175.430 33.300 175.830 33.395 ;
        RECT 174.735 24.260 174.965 33.240 ;
        RECT 176.295 29.225 176.525 33.240 ;
        RECT 176.250 28.275 176.525 29.225 ;
        RECT 217.175 28.390 217.405 31.240 ;
        RECT 221.015 28.390 221.245 31.240 ;
        RECT 176.295 24.260 176.525 28.275 ;
        RECT 217.130 28.010 217.450 28.390 ;
        RECT 220.970 28.010 221.290 28.390 ;
        RECT 217.175 23.260 217.405 28.010 ;
        RECT 221.015 23.260 221.245 28.010 ;
      LAYER Metal2 ;
        RECT 208.380 75.050 210.980 75.100 ;
        RECT 211.330 75.050 213.180 75.120 ;
        RECT 213.480 75.050 215.780 75.110 ;
        RECT 216.080 75.100 222.780 75.150 ;
        RECT 216.080 75.050 225.080 75.100 ;
        RECT 225.430 75.050 227.280 75.120 ;
        RECT 227.580 75.050 229.880 75.110 ;
        RECT 230.250 75.050 230.630 75.060 ;
        RECT 208.380 74.800 230.780 75.050 ;
        RECT 208.480 74.750 230.780 74.800 ;
        RECT 216.080 74.650 222.780 74.750 ;
        RECT 209.460 71.850 214.900 72.150 ;
        RECT 223.560 71.850 229.000 72.150 ;
        RECT 206.930 62.250 217.430 62.550 ;
        RECT 221.030 62.250 231.530 62.550 ;
        RECT 209.460 60.750 218.980 61.050 ;
        RECT 193.080 51.850 206.430 51.900 ;
        RECT 208.380 51.850 210.980 51.900 ;
        RECT 211.330 51.850 213.180 51.920 ;
        RECT 213.480 51.850 215.780 51.910 ;
        RECT 216.080 51.900 222.780 51.950 ;
        RECT 216.080 51.850 225.080 51.900 ;
        RECT 225.430 51.850 227.280 51.920 ;
        RECT 227.580 51.850 229.880 51.910 ;
        RECT 230.250 51.850 230.630 51.860 ;
        RECT 193.080 51.550 230.780 51.850 ;
        RECT 193.080 51.500 206.430 51.550 ;
        RECT 176.390 48.800 176.790 49.200 ;
        RECT 193.080 45.450 193.480 51.500 ;
        RECT 216.080 51.450 222.780 51.550 ;
        RECT 206.930 50.150 218.980 50.450 ;
        RECT 209.460 48.650 214.900 48.950 ;
        RECT 223.560 48.650 229.000 48.950 ;
        RECT 175.130 45.050 193.480 45.450 ;
        RECT 208.790 41.850 229.630 42.150 ;
        RECT 174.470 33.700 174.870 40.850 ;
        RECT 176.390 38.400 176.790 40.600 ;
        RECT 215.610 40.350 224.880 40.650 ;
        RECT 206.860 37.150 231.570 37.450 ;
        RECT 174.470 33.300 175.830 33.700 ;
        RECT 176.180 28.950 176.580 29.225 ;
        RECT 176.155 28.550 176.790 28.950 ;
        RECT 176.180 28.275 176.580 28.550 ;
        RECT 217.100 28.050 221.320 28.350 ;
      LAYER Metal3 ;
        RECT 212.680 62.210 213.080 72.190 ;
        RECT 218.580 50.100 218.980 75.100 ;
        RECT 226.780 62.210 227.180 72.190 ;
        RECT 176.390 28.550 176.790 49.200 ;
        RECT 211.580 41.800 211.980 49.000 ;
        RECT 224.080 40.300 224.480 49.000 ;
        RECT 219.010 27.990 219.410 37.510 ;
  END
END tt_um_ece298_analog_op_amp
END LIBRARY

